VERSION 5.8 ;
BUSBITCHARS "[]" ;
DIVIDERCHAR "/" ;
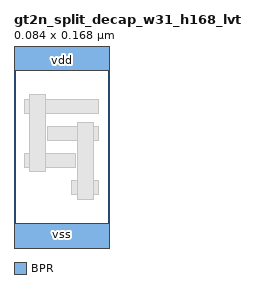
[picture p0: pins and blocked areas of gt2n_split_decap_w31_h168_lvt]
MACRO gt2n_split_decap_w31_h168_lvt
  CLASS CORE ;
  ORIGIN 0 0 ;
  SYMMETRY X Y ;
  SIZE 0.084 BY 0.168 ;
  PIN vss
    DIRECTION INOUT ;
    USE GROUND ;
    PORT
      LAYER BPR ;
        RECT 0 -0.016 0.084 0.016 ;
    END
  END vss
  PIN vdd
    DIRECTION INOUT ;
    USE POWER ;
    PORT
      LAYER BPR ;
        RECT 0 0.152 0.084 0.184 ;
    END
  END vdd
  OBS
    LAYER M0 ;
      RECT 0.051 0.042 0.075 0.054 ;
      RECT 0.009 0.066 0.054 0.078 ;
      RECT 0.03 0.09 0.075 0.102 ;
      RECT 0.009 0.114 0.075 0.126 ;
    LAYER M1 ;
      RECT 0.056 0.038 0.07 0.106 ;
      RECT 0.014 0.062 0.028 0.13 ;
  END
END gt2n_split_decap_w31_h168_lvt
END LIBRARY
